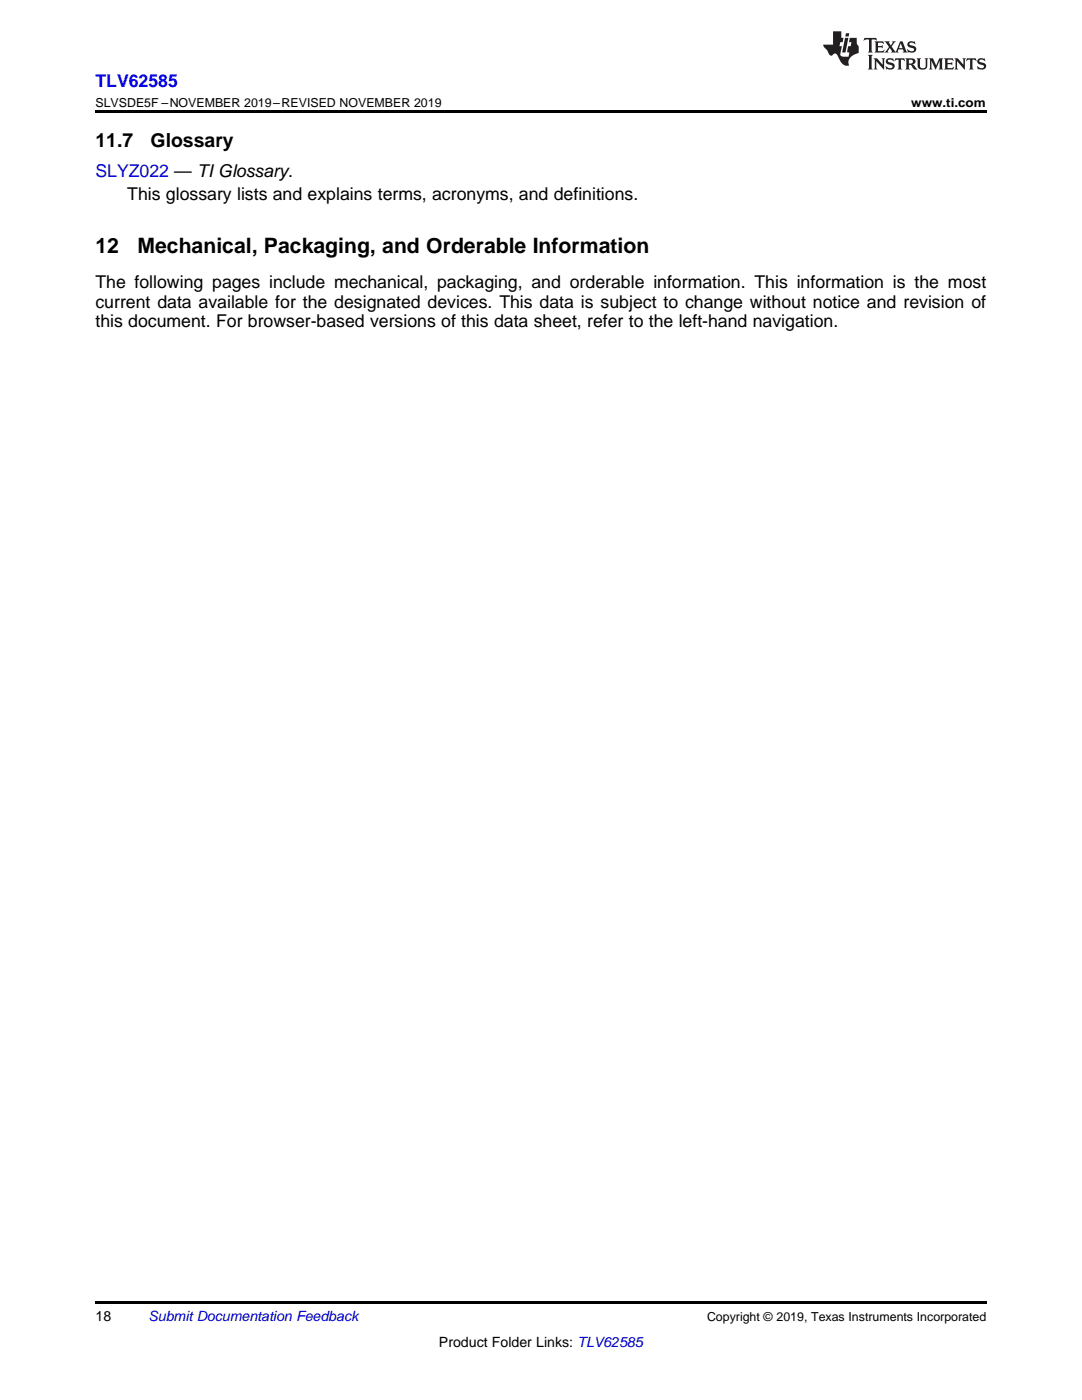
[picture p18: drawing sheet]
<svg xmlns="http://www.w3.org/2000/svg" width="216mm" height="279mm" viewBox="0 0 216 279" stroke-linecap="round" stroke-linejoin="round" font-family="sans-serif">
<defs><g id="words">
<g font-size="4.2">
<text x="19" y="50.5">12</text>
<text x="27.4" y="50.5">Mechanical, Packaging, and Orderable Information</text>
</g>
<g font-size="3.9">
<text x="19" y="29.3">11.7</text>
<text x="30.1" y="29.3">Glossary</text>
</g>
<text font-size="3.5" fill="#00f" x="19" y="17.3">TLV62585</text>
<text font-size="3.5" fill="#0000c8" x="19" y="35.2">SLYZ022 — TI Glossary.</text>
<g font-size="3.5">
<text x="25.4" y="40">This glossary lists and explains terms, acronyms, and definitions.</text>
<text x="19" y="57.5">The following pages include mechanical, packaging, and orderable information. This information is the most</text>
<text x="19" y="61.4">current data available for the designated devices. This data is subject to change without notice and revision of</text>
<text x="19" y="65.3">this document. For browser-based versions of this data sheet, refer to the left-hand navigation.</text>
</g>
<g font-size="2.8">
<text x="19" y="263.6">18</text>
<text x="87.6" y="268.9">Product Folder Links: TLV62585</text>
</g>
<text font-size="2.8" fill="#0000c8" x="29.6" y="263.6">Submit Documentation Feedback</text>
<g font-size="2.5">
<text x="19" y="21.4">SLVSDE5F –NOVEMBER 2019–REVISED NOVEMBER 2019</text>
<text x="181.8" y="21.4">www.ti.com</text>
<text x="141.1" y="263.6">Copyright © 2019, Texas Instruments Incorporated</text>
</g>
</g></defs>
<path d="M19 22h177.8v.5h-177.8zM19 259.7h177.8v.5h-177.8z" fill="#000"/>
<g fill="#231f20">
<path d="M172.5 7.6l-.1 .5 .4-.2h.6v.1v2.1l-.2 .4h.9l-.2-.4v-2.1l.1-.1h.5l.5 .2-.2-.5zM174.5 8.3l.2 .3v1.5l-.2 .4h1.8l.2-.6a1.04 1.04 0 0 1-1.3 .2v-.7h.6l.3 .2v-.6l-.3 .2h-.6v-.6l.8-.1 .4 .3-.2-.5zM176.5 8.3l.9 1.1-.9 1.1h.8l-.2-.2 .4-.7 .5 .7-.2 .2h1.5l-.2-.2 .2-.4h.9l.1 .4-.2 .2h1l-.3-.3-.7-1.9h-.5l-.9 2-.8-1 .9-1h-.8l.1 .3-.4 .5-.3-.6 .1-.2zM179.7 8.6l.4 1h-.7zM181.3 8.4a.63 .63 0 0 0-.2 .7 .63 .63 0 0 0 .6 .4l.6 .2 .1 .2a.75 .75 0 0 1-.7 .4 .75 .75 0 0 1-.6-.5l.1 .7 .1-.1a1.11 1.11 0 0 0 1.5-.6 1.13 1.13 0 0 0-1.2-.8l-.1-.4a1.04 1.04 0 0 1 1.2 .2l-.2-.5-.2 .1-.4-.2zM173.2 10.9l.2 .4v2.2l-.2 .4h1l-.3-.4v-2.2l.3-.4zM174.3 11.6l.3 .4v1.5l-.3 .4h.8l-.2-.4v-1.3l1.5 1.7v-1.9l.2-.4h-.7l.2 .4v.9l-1.1-1.3zM177 11.8a.62 .62 0 0 0-.2 .7 .62 .62 0 0 0 .6 .4l.6 .1 .1 .3a.76 .76 0 0 1-.7 .3 .76 .76 0 0 1-.7-.4l.2 .7 .1-.1a1.11 1.11 0 0 0 1.5-.6 1.13 1.13 0 0 0-1.2-.8l-.1-.4a1.04 1.04 0 0 1 1.2 .2l-.2-.6-.2 .1-.5-.1zM178.7 11.6l-.2 .6a.61 .61 0 0 1 .8-.3v1.6l-.2 .4h.9l-.2-.4v-1.6a.63 .63 0 0 1 .7 .3l-.1-.6zM180.6 11.6l.3 .4v1.5l-.3 .4h1l-.2-.2-.1-.8 .6 .2a.76 .76 0 0 0 1.2 .7l-1-1a.58 .58 0 0 0 .6-.5 .58 .58 0 0 0-.5-.6zM181.4 11.9h.1a.45 .45 0 0 1 .5 .1 .45 .45 0 0 1 .1 .5l-.8 .2zM182.9 11.6l.2 .2a2.17 2.17 0 0 0 .3 1.9 .99 .99 0 0 0 1.6-.6v-1.1l.2-.4h-.7l.2 .2a1.92 1.92 0 0 1-.2 1.8 .6 .6 0 0 1-.9-.5v-1.1l.2-.4zM185.4 11.6l.2 .4v1.5l-.2 .4h.7l-.2-.4v-1.4l.8 1.8 .8-1.8v1.4l-.2 .4h.9l-.2-.4v-1.5l.2-.4h-.8l-.6 1.5-.6-1.5zM188.4 11.6l.2 .4v1.5l-.2 .4h1.8l.1-.6a1.04 1.04 0 0 1-1.2 .1v-.6h.5l.4 .2v-.6l-.4 .2h-.5v-.7h.8l.3 .3-.1-.6zM190.5 11.6l.2 .4v1.5l-.2 .4h.7l-.2-.4v-1.3l1.5 1.7v-1.9l.2-.4h-.7l.2 .4v.9l-1.1-1.3zM192.9 11.6l-.1 .6a.61 .61 0 0 1 .7-.3l.1 1.6-.3 .4h1l-.3-.4 .1-1.6a.63 .63 0 0 1 .7 .3l-.1-.6zM195.2 11.8a.62 .62 0 0 0-.2 .7 .62 .62 0 0 0 .6 .4l.6 .1 .1 .3a.76 .76 0 0 1-.7 .3 .76 .76 0 0 1-.6-.4l.1 .7 .1-.1a1.11 1.11 0 0 0 1.6-.6 1.13 1.13 0 0 0-1.3-.8l-.1-.4a1.04 1.04 0 0 1 1.2 .2l-.1-.6-.2 .1-.5-.1z"/>
<path d="M166.2 6.3v2.6h-1.9v.4l.8 .9a.91 .91 0 0 0 1 .8 .56 .56 0 0 1 .5-.3 .56 .56 0 0 1 .5 .3l.4 .8a1.53 1.53 0 0 0 1.9 1.2 1.54 1.54 0 0 1 1-2.1l.9-.3v-1.4a1.52 1.52 0 0 1-.4-1.6h-1.3l-.2 .8h.5l-.2 .8h-.5l-.1 1v.2l.4 .1-.2 .8a1.93 1.93 0 0 1-1.6-.3l.3-1.8h-.5l.2-.8h.4l.2-.8h-.4v-1.3zM168.6 7.6l-.6 2.9h.7l.6-2.9zM168.8 6.6l-.1 .7h.6l.2-.7z"/>
</g>
<use href="#words"/>
</svg>
